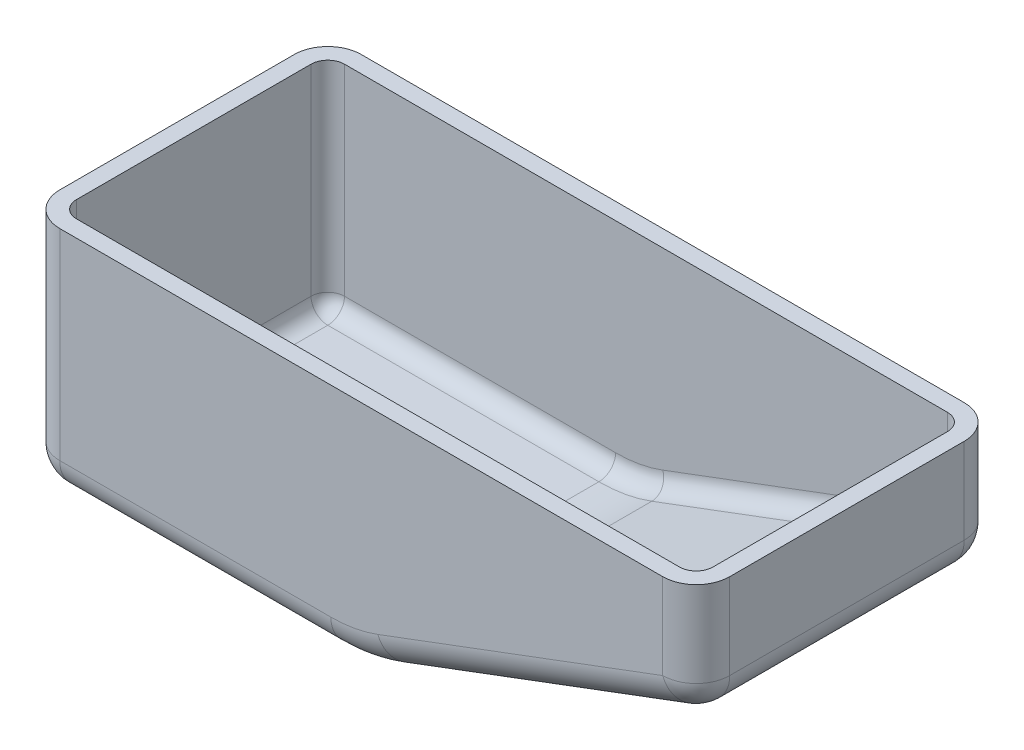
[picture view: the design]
ISO-10303-21;
HEADER;
FILE_DESCRIPTION(('STEP AP214'),'2;1');
FILE_NAME('part.step','',(''),(''),'','','');
FILE_SCHEMA(('AUTOMOTIVE_DESIGN { 1 0 10303 214 1 1 1 1 }'));
ENDSEC;
DATA;
#1=APPLICATION_CONTEXT('core data for automotive mechanical design processes');
#2=APPLICATION_PROTOCOL_DEFINITION('international standard','automotive_design',2000,#1);
#3=PRODUCT_CONTEXT('',#1,'mechanical');
#4=PRODUCT('Part','Part','',(#3));
#5=PRODUCT_RELATED_PRODUCT_CATEGORY('part','',(#4));
#6=PRODUCT_DEFINITION_FORMATION('','',#4);
#7=PRODUCT_DEFINITION_CONTEXT('part definition',#1,'design');
#8=PRODUCT_DEFINITION('design','',#6,#7);
#9=PRODUCT_DEFINITION_SHAPE('','',#8);
#10=(LENGTH_UNIT() NAMED_UNIT(*) SI_UNIT(.MILLI.,.METRE.));
#11=(NAMED_UNIT(*) PLANE_ANGLE_UNIT() SI_UNIT($,.RADIAN.));
#12=(NAMED_UNIT(*) SI_UNIT($,.STERADIAN.) SOLID_ANGLE_UNIT());
#13=UNCERTAINTY_MEASURE_WITH_UNIT(LENGTH_MEASURE(1.E-05),#10,'distance_accuracy_value','');
#14=(GEOMETRIC_REPRESENTATION_CONTEXT(3) GLOBAL_UNCERTAINTY_ASSIGNED_CONTEXT((#13)) GLOBAL_UNIT_ASSIGNED_CONTEXT((#10,
#11,#12)) REPRESENTATION_CONTEXT('',''));
#15=CARTESIAN_POINT('',(0.,0.,0.));
#16=DIRECTION('',(0.,0.,1.));
#17=DIRECTION('',(1.,0.,0.));
#18=AXIS2_PLACEMENT_3D('',#15,#16,#17);
#19=CARTESIAN_POINT('',(0.,0.,22.86));
#20=DIRECTION('',(0.,-1.,0.));
#21=DIRECTION('',(0.,0.,-1.));
#22=AXIS2_PLACEMENT_3D('',#19,#20,#21);
#23=PLANE('',#22);
#24=DIRECTION('',(0.,0.,-1.));
#25=VECTOR('',#24,1.);
#26=CARTESIAN_POINT('',(0.,0.,22.86));
#27=LINE('',#26,#25);
#28=CARTESIAN_POINT('',(0.,0.,17.78));
#29=VERTEX_POINT('',#28);
#30=CARTESIAN_POINT('',(0.,0.,-17.78));
#31=VERTEX_POINT('',#30);
#32=EDGE_CURVE('E352',#29,#31,#27,.T.);
#33=ORIENTED_EDGE('',*,*,#32,.F.);
#34=CARTESIAN_POINT('',(5.08,0.,17.78));
#35=DIRECTION('',(0.,-1.,0.));
#36=DIRECTION('',(0.,0.,-1.));
#37=AXIS2_PLACEMENT_3D('',#34,#35,#36);
#38=CIRCLE('',#37,5.08);
#39=CARTESIAN_POINT('',(5.08,0.,22.86));
#40=VERTEX_POINT('',#39);
#41=EDGE_CURVE('E421',#29,#40,#38,.F.);
#42=ORIENTED_EDGE('',*,*,#41,.T.);
#43=DIRECTION('',(-1.,0.,0.));
#44=VECTOR('',#43,1.);
#45=CARTESIAN_POINT('',(0.,0.,22.86));
#46=LINE('',#45,#44);
#47=CARTESIAN_POINT('',(96.52,0.,22.86));
#48=VERTEX_POINT('',#47);
#49=EDGE_CURVE('E348',#48,#40,#46,.T.);
#50=ORIENTED_EDGE('',*,*,#49,.F.);
#51=CARTESIAN_POINT('',(96.52,0.,17.78));
#52=DIRECTION('',(0.,-1.,0.));
#53=DIRECTION('',(0.,0.,-1.));
#54=AXIS2_PLACEMENT_3D('',#51,#52,#53);
#55=CIRCLE('',#54,5.08);
#56=CARTESIAN_POINT('',(101.6,0.,17.78));
#57=VERTEX_POINT('',#56);
#58=EDGE_CURVE('E418',#48,#57,#55,.F.);
#59=ORIENTED_EDGE('',*,*,#58,.T.);
#60=DIRECTION('',(0.,0.,-1.));
#61=VECTOR('',#60,1.);
#62=CARTESIAN_POINT('',(101.6,0.,22.86));
#63=LINE('',#62,#61);
#64=CARTESIAN_POINT('',(101.6,0.,-17.78));
#65=VERTEX_POINT('',#64);
#66=EDGE_CURVE('E361',#57,#65,#63,.T.);
#67=ORIENTED_EDGE('',*,*,#66,.T.);
#68=CARTESIAN_POINT('',(96.52,0.,-17.78));
#69=DIRECTION('',(0.,-1.,0.));
#70=DIRECTION('',(0.,0.,-1.));
#71=AXIS2_PLACEMENT_3D('',#68,#69,#70);
#72=CIRCLE('',#71,5.08);
#73=CARTESIAN_POINT('',(96.52,0.,-22.86));
#74=VERTEX_POINT('',#73);
#75=EDGE_CURVE('E412',#65,#74,#72,.F.);
#76=ORIENTED_EDGE('',*,*,#75,.T.);
#77=DIRECTION('',(-1.,0.,0.));
#78=VECTOR('',#77,1.);
#79=CARTESIAN_POINT('',(0.,0.,-22.86));
#80=LINE('',#79,#78);
#81=CARTESIAN_POINT('',(5.08,0.,-22.86));
#82=VERTEX_POINT('',#81);
#83=EDGE_CURVE('E353',#74,#82,#80,.T.);
#84=ORIENTED_EDGE('',*,*,#83,.T.);
#85=CARTESIAN_POINT('',(5.08,0.,-17.78));
#86=DIRECTION('',(0.,-1.,0.));
#87=DIRECTION('',(0.,0.,-1.));
#88=AXIS2_PLACEMENT_3D('',#85,#86,#87);
#89=CIRCLE('',#88,5.08);
#90=EDGE_CURVE('E415',#82,#31,#89,.F.);
#91=ORIENTED_EDGE('',*,*,#90,.T.);
#92=EDGE_LOOP('',(#33,#42,#50,#59,#67,#76,#84,#91));
#93=FACE_BOUND('',#92,.T.);
#94=CARTESIAN_POINT('',(5.08,0.,17.78));
#95=DIRECTION('',(0.,-1.,0.));
#96=DIRECTION('',(0.,0.,-1.));
#97=AXIS2_PLACEMENT_3D('',#94,#95,#96);
#98=CIRCLE('',#97,2.54);
#99=CARTESIAN_POINT('',(2.54,0.,17.78));
#100=VERTEX_POINT('',#99);
#101=CARTESIAN_POINT('',(5.08,0.,20.32));
#102=VERTEX_POINT('',#101);
#103=EDGE_CURVE('E327',#100,#102,#98,.F.);
#104=ORIENTED_EDGE('',*,*,#103,.F.);
#105=DIRECTION('',(0.,0.,-1.));
#106=VECTOR('',#105,1.);
#107=CARTESIAN_POINT('',(2.54,0.,22.86));
#108=LINE('',#107,#106);
#109=CARTESIAN_POINT('',(2.54,0.,-17.78));
#110=VERTEX_POINT('',#109);
#111=EDGE_CURVE('E265',#100,#110,#108,.T.);
#112=ORIENTED_EDGE('',*,*,#111,.T.);
#113=CARTESIAN_POINT('',(5.08,0.,-17.78));
#114=DIRECTION('',(0.,-1.,0.));
#115=DIRECTION('',(0.,0.,-1.));
#116=AXIS2_PLACEMENT_3D('',#113,#114,#115);
#117=CIRCLE('',#116,2.54);
#118=CARTESIAN_POINT('',(5.08,0.,-20.32));
#119=VERTEX_POINT('',#118);
#120=EDGE_CURVE('E336',#119,#110,#117,.F.);
#121=ORIENTED_EDGE('',*,*,#120,.F.);
#122=DIRECTION('',(-1.,0.,0.));
#123=VECTOR('',#122,1.);
#124=CARTESIAN_POINT('',(0.,0.,-20.32));
#125=LINE('',#124,#123);
#126=CARTESIAN_POINT('',(96.52,0.,-20.32));
#127=VERTEX_POINT('',#126);
#128=EDGE_CURVE('E64',#127,#119,#125,.T.);
#129=ORIENTED_EDGE('',*,*,#128,.F.);
#130=CARTESIAN_POINT('',(96.52,0.,-17.78));
#131=DIRECTION('',(0.,-1.,0.));
#132=DIRECTION('',(0.,0.,-1.));
#133=AXIS2_PLACEMENT_3D('',#130,#131,#132);
#134=CIRCLE('',#133,2.54);
#135=CARTESIAN_POINT('',(99.06,0.,-17.78));
#136=VERTEX_POINT('',#135);
#137=EDGE_CURVE('E269',#136,#127,#134,.F.);
#138=ORIENTED_EDGE('',*,*,#137,.F.);
#139=DIRECTION('',(0.,0.,-1.));
#140=VECTOR('',#139,1.);
#141=CARTESIAN_POINT('',(99.06,0.,22.86));
#142=LINE('',#141,#140);
#143=CARTESIAN_POINT('',(99.06,0.,17.78));
#144=VERTEX_POINT('',#143);
#145=EDGE_CURVE('E325',#144,#136,#142,.T.);
#146=ORIENTED_EDGE('',*,*,#145,.F.);
#147=CARTESIAN_POINT('',(96.52,0.,17.78));
#148=DIRECTION('',(0.,-1.,0.));
#149=DIRECTION('',(0.,0.,-1.));
#150=AXIS2_PLACEMENT_3D('',#147,#148,#149);
#151=CIRCLE('',#150,2.54);
#152=CARTESIAN_POINT('',(96.52,0.,20.32));
#153=VERTEX_POINT('',#152);
#154=EDGE_CURVE('E330',#153,#144,#151,.F.);
#155=ORIENTED_EDGE('',*,*,#154,.F.);
#156=DIRECTION('',(-1.,0.,0.));
#157=VECTOR('',#156,1.);
#158=CARTESIAN_POINT('',(0.,0.,20.32));
#159=LINE('',#158,#157);
#160=EDGE_CURVE('E326',#153,#102,#159,.T.);
#161=ORIENTED_EDGE('',*,*,#160,.T.);
#162=EDGE_LOOP('',(#104,#112,#121,#129,#138,#146,#155,#161));
#163=FACE_BOUND('',#162,.T.);
#164=ADVANCED_FACE('F46',(#93,#163),#23,.F.);
#165=CARTESIAN_POINT('',(0.,-35.56,22.86));
#166=DIRECTION('',(1.,0.,0.));
#167=DIRECTION('',(0.,0.,-1.));
#168=AXIS2_PLACEMENT_3D('',#165,#166,#167);
#169=PLANE('',#168);
#170=DIRECTION('',(0.,0.,-1.));
#171=VECTOR('',#170,1.);
#172=CARTESIAN_POINT('',(0.,-30.48,22.86));
#173=LINE('',#172,#171);
#174=CARTESIAN_POINT('',(0.,-30.48,-17.78));
#175=VERTEX_POINT('',#174);
#176=CARTESIAN_POINT('',(0.,-30.48,17.78));
#177=VERTEX_POINT('',#176);
#178=EDGE_CURVE('E385',#175,#177,#173,.F.);
#179=ORIENTED_EDGE('',*,*,#178,.T.);
#180=DIRECTION('',(0.,-1.,0.));
#181=VECTOR('',#180,1.);
#182=CARTESIAN_POINT('',(0.,-35.56,17.78));
#183=LINE('',#182,#181);
#184=EDGE_CURVE('E409',#177,#29,#183,.F.);
#185=ORIENTED_EDGE('',*,*,#184,.T.);
#186=ORIENTED_EDGE('',*,*,#32,.T.);
#187=DIRECTION('',(0.,-1.,0.));
#188=VECTOR('',#187,1.);
#189=CARTESIAN_POINT('',(0.,-30.48,-17.78));
#190=LINE('',#189,#188);
#191=EDGE_CURVE('E405',#31,#175,#190,.T.);
#192=ORIENTED_EDGE('',*,*,#191,.T.);
#193=EDGE_LOOP('',(#179,#185,#186,#192));
#194=FACE_BOUND('',#193,.T.);
#195=ADVANCED_FACE('F582',(#194),#169,.F.);
#196=CARTESIAN_POINT('',(50.8,-35.56,22.86));
#197=DIRECTION('',(0.,1.,0.));
#198=DIRECTION('',(-1.,0.,0.));
#199=AXIS2_PLACEMENT_3D('',#196,#197,#198);
#200=PLANE('',#199);
#201=DIRECTION('',(0.,0.,-1.));
#202=VECTOR('',#201,1.);
#203=CARTESIAN_POINT('',(46.1941016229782,-35.56,22.86));
#204=LINE('',#203,#202);
#205=CARTESIAN_POINT('',(46.1941016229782,-35.56,-17.78));
#206=VERTEX_POINT('',#205);
#207=CARTESIAN_POINT('',(46.1941016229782,-35.56,17.78));
#208=VERTEX_POINT('',#207);
#209=EDGE_CURVE('E377',#206,#208,#204,.F.);
#210=ORIENTED_EDGE('',*,*,#209,.T.);
#211=DIRECTION('',(1.,0.,0.));
#212=VECTOR('',#211,1.);
#213=CARTESIAN_POINT('',(50.8,-35.56,17.78));
#214=LINE('',#213,#212);
#215=CARTESIAN_POINT('',(5.08,-35.56,17.78));
#216=VERTEX_POINT('',#215);
#217=EDGE_CURVE('E433',#208,#216,#214,.F.);
#218=ORIENTED_EDGE('',*,*,#217,.T.);
#219=DIRECTION('',(0.,0.,-1.));
#220=VECTOR('',#219,1.);
#221=CARTESIAN_POINT('',(5.08,-35.56,22.86));
#222=LINE('',#221,#220);
#223=CARTESIAN_POINT('',(5.08,-35.56,-17.78));
#224=VERTEX_POINT('',#223);
#225=EDGE_CURVE('E381',#216,#224,#222,.T.);
#226=ORIENTED_EDGE('',*,*,#225,.T.);
#227=DIRECTION('',(1.,0.,0.));
#228=VECTOR('',#227,1.);
#229=CARTESIAN_POINT('',(46.1941016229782,-35.56,-17.78));
#230=LINE('',#229,#228);
#231=EDGE_CURVE('E430',#224,#206,#230,.T.);
#232=ORIENTED_EDGE('',*,*,#231,.T.);
#233=EDGE_LOOP('',(#210,#218,#226,#232));
#234=FACE_BOUND('',#233,.T.);
#235=ADVANCED_FACE('F562',(#234),#200,.F.);
#236=CARTESIAN_POINT('',(101.6,-16.51,22.86));
#237=DIRECTION('',(-0.351123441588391,0.936329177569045,0.));
#238=DIRECTION('',(-0.936329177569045,-0.351123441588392,0.));
#239=AXIS2_PLACEMENT_3D('',#236,#237,#238);
#240=PLANE('',#239);
#241=DIRECTION('',(0.,0.,-1.));
#242=VECTOR('',#241,1.);
#243=CARTESIAN_POINT('',(55.1126370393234,-33.9427611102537,22.86));
#244=LINE('',#243,#242);
#245=CARTESIAN_POINT('',(55.1126370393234,-33.9427611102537,17.78));
#246=VERTEX_POINT('',#245);
#247=CARTESIAN_POINT('',(55.1126370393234,-33.9427611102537,-17.78));
#248=VERTEX_POINT('',#247);
#249=EDGE_CURVE('E369',#246,#248,#244,.T.);
#250=ORIENTED_EDGE('',*,*,#249,.T.);
#251=DIRECTION('',(0.936329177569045,0.351123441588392,0.));
#252=VECTOR('',#251,1.);
#253=CARTESIAN_POINT('',(98.303707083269,-17.7461098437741,-17.78));
#254=LINE('',#253,#252);
#255=CARTESIAN_POINT('',(98.303707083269,-17.7461098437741,-17.78));
#256=VERTEX_POINT('',#255);
#257=EDGE_CURVE('E12',#248,#256,#254,.T.);
#258=ORIENTED_EDGE('',*,*,#257,.T.);
#259=DIRECTION('',(0.,0.,-1.));
#260=VECTOR('',#259,1.);
#261=CARTESIAN_POINT('',(98.303707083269,-17.7461098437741,22.86));
#262=LINE('',#261,#260);
#263=CARTESIAN_POINT('',(98.303707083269,-17.7461098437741,17.78));
#264=VERTEX_POINT('',#263);
#265=EDGE_CURVE('E373',#256,#264,#262,.F.);
#266=ORIENTED_EDGE('',*,*,#265,.T.);
#267=DIRECTION('',(0.936329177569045,0.351123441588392,0.));
#268=VECTOR('',#267,1.);
#269=CARTESIAN_POINT('',(101.6,-16.51,17.78));
#270=LINE('',#269,#268);
#271=EDGE_CURVE('E56',#264,#246,#270,.F.);
#272=ORIENTED_EDGE('',*,*,#271,.T.);
#273=EDGE_LOOP('',(#250,#258,#266,#272));
#274=FACE_BOUND('',#273,.T.);
#275=ADVANCED_FACE('F542',(#274),#240,.F.);
#276=CARTESIAN_POINT('',(101.6,0.,22.86));
#277=DIRECTION('',(-1.,0.,0.));
#278=DIRECTION('',(0.,0.,1.));
#279=AXIS2_PLACEMENT_3D('',#276,#277,#278);
#280=PLANE('',#279);
#281=ORIENTED_EDGE('',*,*,#66,.F.);
#282=DIRECTION('',(0.,1.,0.));
#283=VECTOR('',#282,1.);
#284=CARTESIAN_POINT('',(101.6,0.,17.78));
#285=LINE('',#284,#283);
#286=CARTESIAN_POINT('',(101.6,-12.9895576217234,17.78));
#287=VERTEX_POINT('',#286);
#288=EDGE_CURVE('E445',#57,#287,#285,.F.);
#289=ORIENTED_EDGE('',*,*,#288,.T.);
#290=DIRECTION('',(0.,0.,-1.));
#291=VECTOR('',#290,1.);
#292=CARTESIAN_POINT('',(101.6,-12.9895576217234,22.86));
#293=LINE('',#292,#291);
#294=CARTESIAN_POINT('',(101.6,-12.9895576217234,-17.78));
#295=VERTEX_POINT('',#294);
#296=EDGE_CURVE('E365',#287,#295,#293,.T.);
#297=ORIENTED_EDGE('',*,*,#296,.T.);
#298=DIRECTION('',(0.,1.,0.));
#299=VECTOR('',#298,1.);
#300=CARTESIAN_POINT('',(101.6,0.,-17.78));
#301=LINE('',#300,#299);
#302=EDGE_CURVE('E442',#295,#65,#301,.T.);
#303=ORIENTED_EDGE('',*,*,#302,.T.);
#304=EDGE_LOOP('',(#281,#289,#297,#303));
#305=FACE_BOUND('',#304,.T.);
#306=ADVANCED_FACE('F524',(#305),#280,.F.);
#307=CARTESIAN_POINT('',(0.,0.,22.86));
#308=DIRECTION('',(0.,0.,-1.));
#309=DIRECTION('',(-1.,0.,0.));
#310=AXIS2_PLACEMENT_3D('',#307,#308,#309);
#311=PLANE('',#310);
#312=ORIENTED_EDGE('',*,*,#49,.T.);
#313=DIRECTION('',(0.,-1.,0.));
#314=VECTOR('',#313,1.);
#315=CARTESIAN_POINT('',(5.08,0.,22.86));
#316=LINE('',#315,#314);
#317=CARTESIAN_POINT('',(5.08,-30.48,22.86));
#318=VERTEX_POINT('',#317);
#319=EDGE_CURVE('E401',#40,#318,#316,.T.);
#320=ORIENTED_EDGE('',*,*,#319,.T.);
#321=DIRECTION('',(1.,0.,0.));
#322=VECTOR('',#321,1.);
#323=CARTESIAN_POINT('',(0.,-30.48,22.86));
#324=LINE('',#323,#322);
#325=CARTESIAN_POINT('',(46.1941016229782,-30.48,22.86));
#326=VERTEX_POINT('',#325);
#327=EDGE_CURVE('E398',#318,#326,#324,.T.);
#328=ORIENTED_EDGE('',*,*,#327,.T.);
#329=CARTESIAN_POINT('',(46.1941016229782,-10.16,22.86));
#330=DIRECTION('',(0.,0.,-1.));
#331=DIRECTION('',(-1.,0.,0.));
#332=AXIS2_PLACEMENT_3D('',#329,#330,#331);
#333=CIRCLE('',#332,20.32);
#334=CARTESIAN_POINT('',(53.3289299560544,-29.186208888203,22.86));
#335=VERTEX_POINT('',#334);
#336=EDGE_CURVE('E395',#326,#335,#333,.F.);
#337=ORIENTED_EDGE('',*,*,#336,.T.);
#338=DIRECTION('',(0.936329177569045,0.351123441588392,0.));
#339=VECTOR('',#338,1.);
#340=CARTESIAN_POINT('',(16.1702655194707,-43.1207080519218,22.86));
#341=LINE('',#340,#339);
#342=CARTESIAN_POINT('',(96.52,-12.9895576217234,22.86));
#343=VERTEX_POINT('',#342);
#344=EDGE_CURVE('E389',#335,#343,#341,.T.);
#345=ORIENTED_EDGE('',*,*,#344,.T.);
#346=DIRECTION('',(0.,1.,0.));
#347=VECTOR('',#346,1.);
#348=CARTESIAN_POINT('',(96.52,0.,22.86));
#349=LINE('',#348,#347);
#350=EDGE_CURVE('E392',#343,#48,#349,.T.);
#351=ORIENTED_EDGE('',*,*,#350,.T.);
#352=EDGE_LOOP('',(#312,#320,#328,#337,#345,#351));
#353=FACE_BOUND('',#352,.T.);
#354=ADVANCED_FACE('F597',(#353),#311,.F.);
#355=CARTESIAN_POINT('',(0.,0.,-22.86));
#356=DIRECTION('',(0.,0.,-1.));
#357=DIRECTION('',(-1.,0.,0.));
#358=AXIS2_PLACEMENT_3D('',#355,#356,#357);
#359=PLANE('',#358);
#360=DIRECTION('',(1.,0.,0.));
#361=VECTOR('',#360,1.);
#362=CARTESIAN_POINT('',(5.08,-30.48,-22.86));
#363=LINE('',#362,#361);
#364=CARTESIAN_POINT('',(46.1941016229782,-30.48,-22.86));
#365=VERTEX_POINT('',#364);
#366=CARTESIAN_POINT('',(5.08,-30.48,-22.86));
#367=VERTEX_POINT('',#366);
#368=EDGE_CURVE('E454',#365,#367,#363,.F.);
#369=ORIENTED_EDGE('',*,*,#368,.T.);
#370=DIRECTION('',(0.,-1.,0.));
#371=VECTOR('',#370,1.);
#372=CARTESIAN_POINT('',(5.08,0.,-22.86));
#373=LINE('',#372,#371);
#374=EDGE_CURVE('E465',#367,#82,#373,.F.);
#375=ORIENTED_EDGE('',*,*,#374,.T.);
#376=ORIENTED_EDGE('',*,*,#83,.F.);
#377=DIRECTION('',(0.,1.,0.));
#378=VECTOR('',#377,1.);
#379=CARTESIAN_POINT('',(96.52,-12.9895576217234,-22.86));
#380=LINE('',#379,#378);
#381=CARTESIAN_POINT('',(96.52,-12.9895576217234,-22.86));
#382=VERTEX_POINT('',#381);
#383=EDGE_CURVE('E72',#74,#382,#380,.F.);
#384=ORIENTED_EDGE('',*,*,#383,.T.);
#385=DIRECTION('',(0.936329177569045,0.351123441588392,0.));
#386=VECTOR('',#385,1.);
#387=CARTESIAN_POINT('',(53.3289299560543,-29.186208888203,-22.86));
#388=LINE('',#387,#386);
#389=CARTESIAN_POINT('',(53.3289299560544,-29.186208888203,-22.86));
#390=VERTEX_POINT('',#389);
#391=EDGE_CURVE('E460',#382,#390,#388,.F.);
#392=ORIENTED_EDGE('',*,*,#391,.T.);
#393=CARTESIAN_POINT('',(46.1941016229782,-10.16,-22.86));
#394=DIRECTION('',(0.,0.,-1.));
#395=DIRECTION('',(-1.,0.,0.));
#396=AXIS2_PLACEMENT_3D('',#393,#394,#395);
#397=CIRCLE('',#396,20.32);
#398=EDGE_CURVE('E457',#390,#365,#397,.T.);
#399=ORIENTED_EDGE('',*,*,#398,.T.);
#400=EDGE_LOOP('',(#369,#375,#376,#384,#392,#399));
#401=FACE_BOUND('',#400,.T.);
#402=ADVANCED_FACE('F579',(#401),#359,.T.);
#403=CARTESIAN_POINT('',(96.52,-12.9895576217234,22.86));
#404=DIRECTION('',(0.,0.,-1.));
#405=DIRECTION('',(-1.,0.,0.));
#406=AXIS2_PLACEMENT_3D('',#403,#404,#405);
#407=CYLINDRICAL_SURFACE('',#406,5.08);
#408=ORIENTED_EDGE('',*,*,#296,.F.);
#409=CARTESIAN_POINT('',(96.52,-12.9895576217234,17.78));
#410=DIRECTION('',(0.,0.,-1.));
#411=DIRECTION('',(-1.,0.,0.));
#412=AXIS2_PLACEMENT_3D('',#409,#410,#411);
#413=CIRCLE('',#412,5.08);
#414=EDGE_CURVE('E451',#287,#264,#413,.T.);
#415=ORIENTED_EDGE('',*,*,#414,.T.);
#416=ORIENTED_EDGE('',*,*,#265,.F.);
#417=CARTESIAN_POINT('',(96.52,-12.9895576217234,-17.78));
#418=DIRECTION('',(0.,0.,-1.));
#419=DIRECTION('',(-1.,0.,0.));
#420=AXIS2_PLACEMENT_3D('',#417,#418,#419);
#421=CIRCLE('',#420,5.08);
#422=EDGE_CURVE('E448',#256,#295,#421,.F.);
#423=ORIENTED_EDGE('',*,*,#422,.T.);
#424=EDGE_LOOP('',(#408,#415,#416,#423));
#425=FACE_BOUND('',#424,.T.);
#426=ADVANCED_FACE('F538',(#425),#407,.T.);
#427=CARTESIAN_POINT('',(5.08,-30.48,22.86));
#428=DIRECTION('',(0.,0.,-1.));
#429=DIRECTION('',(-1.,0.,0.));
#430=AXIS2_PLACEMENT_3D('',#427,#428,#429);
#431=CYLINDRICAL_SURFACE('',#430,5.08);
#432=ORIENTED_EDGE('',*,*,#225,.F.);
#433=CARTESIAN_POINT('',(5.08,-30.48,17.78));
#434=DIRECTION('',(0.,0.,-1.));
#435=DIRECTION('',(-1.,0.,0.));
#436=AXIS2_PLACEMENT_3D('',#433,#434,#435);
#437=CIRCLE('',#436,5.08);
#438=EDGE_CURVE('E427',#216,#177,#437,.T.);
#439=ORIENTED_EDGE('',*,*,#438,.T.);
#440=ORIENTED_EDGE('',*,*,#178,.F.);
#441=CARTESIAN_POINT('',(5.08,-30.48,-17.78));
#442=DIRECTION('',(0.,0.,-1.));
#443=DIRECTION('',(-1.,0.,0.));
#444=AXIS2_PLACEMENT_3D('',#441,#442,#443);
#445=CIRCLE('',#444,5.08);
#446=EDGE_CURVE('E424',#175,#224,#445,.F.);
#447=ORIENTED_EDGE('',*,*,#446,.T.);
#448=EDGE_LOOP('',(#432,#439,#440,#447));
#449=FACE_BOUND('',#448,.T.);
#450=ADVANCED_FACE('F620',(#449),#431,.T.);
#451=CARTESIAN_POINT('',(46.1941016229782,-10.16,22.86));
#452=DIRECTION('',(0.,0.,-1.));
#453=DIRECTION('',(-1.,0.,0.));
#454=AXIS2_PLACEMENT_3D('',#451,#452,#453);
#455=CYLINDRICAL_SURFACE('',#454,25.4);
#456=ORIENTED_EDGE('',*,*,#249,.F.);
#457=CARTESIAN_POINT('',(46.1941016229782,-10.16,17.78));
#458=DIRECTION('',(0.,0.,-1.));
#459=DIRECTION('',(-1.,0.,0.));
#460=AXIS2_PLACEMENT_3D('',#457,#458,#459);
#461=CIRCLE('',#460,25.4);
#462=EDGE_CURVE('E439',#246,#208,#461,.T.);
#463=ORIENTED_EDGE('',*,*,#462,.T.);
#464=ORIENTED_EDGE('',*,*,#209,.F.);
#465=CARTESIAN_POINT('',(46.1941016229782,-10.16,-17.78));
#466=DIRECTION('',(0.,0.,-1.));
#467=DIRECTION('',(-1.,0.,0.));
#468=AXIS2_PLACEMENT_3D('',#465,#466,#467);
#469=CIRCLE('',#468,25.4);
#470=EDGE_CURVE('E436',#206,#248,#469,.F.);
#471=ORIENTED_EDGE('',*,*,#470,.T.);
#472=EDGE_LOOP('',(#456,#463,#464,#471));
#473=FACE_BOUND('',#472,.T.);
#474=ADVANCED_FACE('F559',(#473),#455,.T.);
#475=CARTESIAN_POINT('',(96.52,0.,17.78));
#476=DIRECTION('',(0.,1.,0.));
#477=DIRECTION('',(0.,0.,1.));
#478=AXIS2_PLACEMENT_3D('',#475,#476,#477);
#479=CYLINDRICAL_SURFACE('',#478,5.08);
#480=CARTESIAN_POINT('',(96.52,-12.9895576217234,17.78));
#481=DIRECTION('',(0.,-1.,0.));
#482=DIRECTION('',(0.,0.,-1.));
#483=AXIS2_PLACEMENT_3D('',#480,#481,#482);
#484=CIRCLE('',#483,5.08);
#485=EDGE_CURVE('E357',#287,#343,#484,.T.);
#486=ORIENTED_EDGE('',*,*,#485,.F.);
#487=ORIENTED_EDGE('',*,*,#288,.F.);
#488=ORIENTED_EDGE('',*,*,#58,.F.);
#489=ORIENTED_EDGE('',*,*,#350,.F.);
#490=EDGE_LOOP('',(#486,#487,#488,#489));
#491=FACE_BOUND('',#490,.T.);
#492=ADVANCED_FACE('F535',(#491),#479,.T.);
#493=CARTESIAN_POINT('',(96.52,-12.9895576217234,17.78));
#494=DIRECTION('',(0.,0.,-1.));
#495=DIRECTION('',(-1.,0.,0.));
#496=AXIS2_PLACEMENT_3D('',#493,#494,#495);
#497=SPHERICAL_SURFACE('',#496,5.08);
#498=ORIENTED_EDGE('',*,*,#414,.F.);
#499=ORIENTED_EDGE('',*,*,#485,.T.);
#500=CARTESIAN_POINT('',(96.52,-12.9895576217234,17.78));
#501=DIRECTION('',(-0.936329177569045,-0.351123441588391,0.));
#502=DIRECTION('',(0.351123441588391,-0.936329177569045,0.));
#503=AXIS2_PLACEMENT_3D('',#500,#501,#502);
#504=CIRCLE('',#503,5.08);
#505=EDGE_CURVE('E485',#264,#343,#504,.T.);
#506=ORIENTED_EDGE('',*,*,#505,.F.);
#507=EDGE_LOOP('',(#498,#499,#506));
#508=FACE_BOUND('',#507,.T.);
#509=ADVANCED_FACE('F546',(#508),#497,.T.);
#510=CARTESIAN_POINT('',(16.1702655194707,-43.1207080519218,17.78));
#511=DIRECTION('',(0.936329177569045,0.351123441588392,0.));
#512=DIRECTION('',(-0.351123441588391,0.936329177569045,0.));
#513=AXIS2_PLACEMENT_3D('',#510,#511,#512);
#514=CYLINDRICAL_SURFACE('',#513,5.08);
#515=ORIENTED_EDGE('',*,*,#505,.T.);
#516=ORIENTED_EDGE('',*,*,#344,.F.);
#517=CARTESIAN_POINT('',(53.3289299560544,-29.186208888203,17.78));
#518=DIRECTION('',(-0.936329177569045,-0.351123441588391,0.));
#519=DIRECTION('',(0.351123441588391,-0.936329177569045,0.));
#520=AXIS2_PLACEMENT_3D('',#517,#518,#519);
#521=CIRCLE('',#520,5.08);
#522=EDGE_CURVE('E481',#246,#335,#521,.T.);
#523=ORIENTED_EDGE('',*,*,#522,.F.);
#524=ORIENTED_EDGE('',*,*,#271,.F.);
#525=EDGE_LOOP('',(#515,#516,#523,#524));
#526=FACE_BOUND('',#525,.T.);
#527=ADVANCED_FACE('F550',(#526),#514,.T.);
#528=CARTESIAN_POINT('',(46.1941016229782,-10.16,17.78));
#529=DIRECTION('',(0.,0.,-1.));
#530=DIRECTION('',(-1.,0.,0.));
#531=AXIS2_PLACEMENT_3D('',#528,#529,#530);
#532=TOROIDAL_SURFACE('',#531,20.32,5.08);
#533=ORIENTED_EDGE('',*,*,#522,.T.);
#534=ORIENTED_EDGE('',*,*,#336,.F.);
#535=CARTESIAN_POINT('',(46.1941016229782,-30.48,17.78));
#536=DIRECTION('',(-1.,0.,0.));
#537=DIRECTION('',(0.,0.,1.));
#538=AXIS2_PLACEMENT_3D('',#535,#536,#537);
#539=CIRCLE('',#538,5.08);
#540=EDGE_CURVE('E477',#208,#326,#539,.T.);
#541=ORIENTED_EDGE('',*,*,#540,.F.);
#542=ORIENTED_EDGE('',*,*,#462,.F.);
#543=EDGE_LOOP('',(#533,#534,#541,#542));
#544=FACE_BOUND('',#543,.T.);
#545=ADVANCED_FACE('F555',(#544),#532,.T.);
#546=CARTESIAN_POINT('',(0.,-30.48,17.78));
#547=DIRECTION('',(1.,0.,0.));
#548=DIRECTION('',(0.,1.,0.));
#549=AXIS2_PLACEMENT_3D('',#546,#547,#548);
#550=CYLINDRICAL_SURFACE('',#549,5.08);
#551=CARTESIAN_POINT('',(5.08,-30.48,17.78));
#552=DIRECTION('',(-1.,0.,0.));
#553=DIRECTION('',(0.,0.,1.));
#554=AXIS2_PLACEMENT_3D('',#551,#552,#553);
#555=CIRCLE('',#554,5.08);
#556=EDGE_CURVE('E473',#216,#318,#555,.T.);
#557=ORIENTED_EDGE('',*,*,#556,.F.);
#558=ORIENTED_EDGE('',*,*,#217,.F.);
#559=ORIENTED_EDGE('',*,*,#540,.T.);
#560=ORIENTED_EDGE('',*,*,#327,.F.);
#561=EDGE_LOOP('',(#557,#558,#559,#560));
#562=FACE_BOUND('',#561,.T.);
#563=ADVANCED_FACE('F595',(#562),#550,.T.);
#564=CARTESIAN_POINT('',(5.08,-30.48,17.78));
#565=DIRECTION('',(0.,0.,-1.));
#566=DIRECTION('',(-1.,0.,0.));
#567=AXIS2_PLACEMENT_3D('',#564,#565,#566);
#568=SPHERICAL_SURFACE('',#567,5.08);
#569=ORIENTED_EDGE('',*,*,#438,.F.);
#570=ORIENTED_EDGE('',*,*,#556,.T.);
#571=CARTESIAN_POINT('',(5.08,-30.48,17.78));
#572=DIRECTION('',(0.,1.,0.));
#573=DIRECTION('',(0.,0.,1.));
#574=AXIS2_PLACEMENT_3D('',#571,#572,#573);
#575=CIRCLE('',#574,5.08);
#576=EDGE_CURVE('E470',#177,#318,#575,.T.);
#577=ORIENTED_EDGE('',*,*,#576,.F.);
#578=EDGE_LOOP('',(#569,#570,#577));
#579=FACE_BOUND('',#578,.T.);
#580=ADVANCED_FACE('F591',(#579),#568,.T.);
#581=CARTESIAN_POINT('',(5.08,0.,17.78));
#582=DIRECTION('',(0.,-1.,0.));
#583=DIRECTION('',(0.,0.,-1.));
#584=AXIS2_PLACEMENT_3D('',#581,#582,#583);
#585=CYLINDRICAL_SURFACE('',#584,5.08);
#586=ORIENTED_EDGE('',*,*,#41,.F.);
#587=ORIENTED_EDGE('',*,*,#184,.F.);
#588=ORIENTED_EDGE('',*,*,#576,.T.);
#589=ORIENTED_EDGE('',*,*,#319,.F.);
#590=EDGE_LOOP('',(#586,#587,#588,#589));
#591=FACE_BOUND('',#590,.T.);
#592=ADVANCED_FACE('F587',(#591),#585,.T.);
#593=CARTESIAN_POINT('',(96.52,0.,-17.78));
#594=DIRECTION('',(0.,-1.,0.));
#595=DIRECTION('',(0.,0.,-1.));
#596=AXIS2_PLACEMENT_3D('',#593,#594,#595);
#597=CYLINDRICAL_SURFACE('',#596,5.08);
#598=ORIENTED_EDGE('',*,*,#75,.F.);
#599=ORIENTED_EDGE('',*,*,#302,.F.);
#600=CARTESIAN_POINT('',(96.52,-12.9895576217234,-17.78));
#601=DIRECTION('',(0.,-1.,0.));
#602=DIRECTION('',(0.,0.,-1.));
#603=AXIS2_PLACEMENT_3D('',#600,#601,#602);
#604=CIRCLE('',#603,5.08);
#605=EDGE_CURVE('E50',#382,#295,#604,.T.);
#606=ORIENTED_EDGE('',*,*,#605,.F.);
#607=ORIENTED_EDGE('',*,*,#383,.F.);
#608=EDGE_LOOP('',(#598,#599,#606,#607));
#609=FACE_BOUND('',#608,.T.);
#610=ADVANCED_FACE('F48',(#609),#597,.T.);
#611=CARTESIAN_POINT('',(96.52,-12.9895576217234,-17.78));
#612=DIRECTION('',(0.,0.,-1.));
#613=DIRECTION('',(-1.,0.,0.));
#614=AXIS2_PLACEMENT_3D('',#611,#612,#613);
#615=SPHERICAL_SURFACE('',#614,5.08);
#616=ORIENTED_EDGE('',*,*,#605,.T.);
#617=ORIENTED_EDGE('',*,*,#422,.F.);
#618=CARTESIAN_POINT('',(96.52,-12.9895576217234,-17.78));
#619=DIRECTION('',(-0.936329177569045,-0.351123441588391,0.));
#620=DIRECTION('',(0.351123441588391,-0.936329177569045,0.));
#621=AXIS2_PLACEMENT_3D('',#618,#619,#620);
#622=CIRCLE('',#621,5.08);
#623=EDGE_CURVE('E507',#382,#256,#622,.T.);
#624=ORIENTED_EDGE('',*,*,#623,.F.);
#625=EDGE_LOOP('',(#616,#617,#624));
#626=FACE_BOUND('',#625,.T.);
#627=ADVANCED_FACE('F518',(#626),#615,.T.);
#628=CARTESIAN_POINT('',(99.816292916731,-11.7534477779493,-17.78));
#629=DIRECTION('',(-0.936329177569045,-0.351123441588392,0.));
#630=DIRECTION('',(0.351123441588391,-0.936329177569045,0.));
#631=AXIS2_PLACEMENT_3D('',#628,#629,#630);
#632=CYLINDRICAL_SURFACE('',#631,5.08);
#633=ORIENTED_EDGE('',*,*,#623,.T.);
#634=ORIENTED_EDGE('',*,*,#257,.F.);
#635=CARTESIAN_POINT('',(53.3289299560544,-29.186208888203,-17.78));
#636=DIRECTION('',(-0.936329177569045,-0.351123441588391,0.));
#637=DIRECTION('',(0.351123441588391,-0.936329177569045,0.));
#638=AXIS2_PLACEMENT_3D('',#635,#636,#637);
#639=CIRCLE('',#638,5.08);
#640=EDGE_CURVE('E504',#390,#248,#639,.T.);
#641=ORIENTED_EDGE('',*,*,#640,.F.);
#642=ORIENTED_EDGE('',*,*,#391,.F.);
#643=EDGE_LOOP('',(#633,#634,#641,#642));
#644=FACE_BOUND('',#643,.T.);
#645=ADVANCED_FACE('F649',(#644),#632,.T.);
#646=CARTESIAN_POINT('',(46.1941016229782,-10.16,-17.78));
#647=DIRECTION('',(0.,0.,-1.));
#648=DIRECTION('',(-1.,0.,0.));
#649=AXIS2_PLACEMENT_3D('',#646,#647,#648);
#650=TOROIDAL_SURFACE('',#649,20.32,5.08);
#651=ORIENTED_EDGE('',*,*,#640,.T.);
#652=ORIENTED_EDGE('',*,*,#470,.F.);
#653=CARTESIAN_POINT('',(46.1941016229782,-30.48,-17.78));
#654=DIRECTION('',(-1.,0.,0.));
#655=DIRECTION('',(0.,0.,1.));
#656=AXIS2_PLACEMENT_3D('',#653,#654,#655);
#657=CIRCLE('',#656,5.08);
#658=EDGE_CURVE('E500',#365,#206,#657,.T.);
#659=ORIENTED_EDGE('',*,*,#658,.F.);
#660=ORIENTED_EDGE('',*,*,#398,.F.);
#661=EDGE_LOOP('',(#651,#652,#659,#660));
#662=FACE_BOUND('',#661,.T.);
#663=ADVANCED_FACE('F646',(#662),#650,.T.);
#664=CARTESIAN_POINT('',(50.8,-30.48,-17.78));
#665=DIRECTION('',(-1.,0.,0.));
#666=DIRECTION('',(0.,-1.,0.));
#667=AXIS2_PLACEMENT_3D('',#664,#665,#666);
#668=CYLINDRICAL_SURFACE('',#667,5.08);
#669=ORIENTED_EDGE('',*,*,#658,.T.);
#670=ORIENTED_EDGE('',*,*,#231,.F.);
#671=CARTESIAN_POINT('',(5.08,-30.48,-17.78));
#672=DIRECTION('',(-1.,0.,0.));
#673=DIRECTION('',(0.,0.,1.));
#674=AXIS2_PLACEMENT_3D('',#671,#672,#673);
#675=CIRCLE('',#674,5.08);
#676=EDGE_CURVE('E495',#367,#224,#675,.T.);
#677=ORIENTED_EDGE('',*,*,#676,.F.);
#678=ORIENTED_EDGE('',*,*,#368,.F.);
#679=EDGE_LOOP('',(#669,#670,#677,#678));
#680=FACE_BOUND('',#679,.T.);
#681=ADVANCED_FACE('F567',(#680),#668,.T.);
#682=CARTESIAN_POINT('',(5.08,-30.48,-17.78));
#683=DIRECTION('',(0.,0.,-1.));
#684=DIRECTION('',(-1.,0.,0.));
#685=AXIS2_PLACEMENT_3D('',#682,#683,#684);
#686=SPHERICAL_SURFACE('',#685,5.08);
#687=ORIENTED_EDGE('',*,*,#676,.T.);
#688=ORIENTED_EDGE('',*,*,#446,.F.);
#689=CARTESIAN_POINT('',(5.08,-30.48,-17.78));
#690=DIRECTION('',(0.,1.,0.));
#691=DIRECTION('',(0.,0.,1.));
#692=AXIS2_PLACEMENT_3D('',#689,#690,#691);
#693=CIRCLE('',#692,5.08);
#694=EDGE_CURVE('E492',#367,#175,#693,.T.);
#695=ORIENTED_EDGE('',*,*,#694,.F.);
#696=EDGE_LOOP('',(#687,#688,#695));
#697=FACE_BOUND('',#696,.T.);
#698=ADVANCED_FACE('F574',(#697),#686,.T.);
#699=CARTESIAN_POINT('',(5.08,-35.56,-17.78));
#700=DIRECTION('',(0.,1.,0.));
#701=DIRECTION('',(0.,0.,1.));
#702=AXIS2_PLACEMENT_3D('',#699,#700,#701);
#703=CYLINDRICAL_SURFACE('',#702,5.08);
#704=ORIENTED_EDGE('',*,*,#90,.F.);
#705=ORIENTED_EDGE('',*,*,#374,.F.);
#706=ORIENTED_EDGE('',*,*,#694,.T.);
#707=ORIENTED_EDGE('',*,*,#191,.F.);
#708=EDGE_LOOP('',(#704,#705,#706,#707));
#709=FACE_BOUND('',#708,.T.);
#710=ADVANCED_FACE('F578',(#709),#703,.T.);
#711=CARTESIAN_POINT('',(2.54,-35.56,22.86));
#712=DIRECTION('',(1.,0.,0.));
#713=DIRECTION('',(0.,0.,-1.));
#714=AXIS2_PLACEMENT_3D('',#711,#712,#713);
#715=PLANE('',#714);
#716=DIRECTION('',(0.,0.,-1.));
#717=VECTOR('',#716,1.);
#718=CARTESIAN_POINT('',(2.54,-30.48,22.86));
#719=LINE('',#718,#717);
#720=CARTESIAN_POINT('',(2.54,-30.48,-17.78));
#721=VERTEX_POINT('',#720);
#722=CARTESIAN_POINT('',(2.54,-30.48,17.78));
#723=VERTEX_POINT('',#722);
#724=EDGE_CURVE('E251',#721,#723,#719,.F.);
#725=ORIENTED_EDGE('',*,*,#724,.F.);
#726=DIRECTION('',(0.,1.,0.));
#727=VECTOR('',#726,1.);
#728=CARTESIAN_POINT('',(2.54,-35.56,-17.78));
#729=LINE('',#728,#727);
#730=EDGE_CURVE('E270',#110,#721,#729,.F.);
#731=ORIENTED_EDGE('',*,*,#730,.F.);
#732=ORIENTED_EDGE('',*,*,#111,.F.);
#733=DIRECTION('',(0.,1.,0.));
#734=VECTOR('',#733,1.);
#735=CARTESIAN_POINT('',(2.54,-35.56,17.78));
#736=LINE('',#735,#734);
#737=EDGE_CURVE('E262',#723,#100,#736,.T.);
#738=ORIENTED_EDGE('',*,*,#737,.F.);
#739=EDGE_LOOP('',(#725,#731,#732,#738));
#740=FACE_BOUND('',#739,.T.);
#741=ADVANCED_FACE('F263',(#740),#715,.T.);
#742=CARTESIAN_POINT('',(50.8,-33.02,22.86));
#743=DIRECTION('',(0.,1.,0.));
#744=DIRECTION('',(-1.,0.,0.));
#745=AXIS2_PLACEMENT_3D('',#742,#743,#744);
#746=PLANE('',#745);
#747=DIRECTION('',(0.,0.,1.));
#748=VECTOR('',#747,1.);
#749=CARTESIAN_POINT('',(46.1941016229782,-33.02,22.86));
#750=LINE('',#749,#748);
#751=CARTESIAN_POINT('',(46.1941016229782,-33.02,-17.78));
#752=VERTEX_POINT('',#751);
#753=CARTESIAN_POINT('',(46.1941016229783,-33.02,17.78));
#754=VERTEX_POINT('',#753);
#755=EDGE_CURVE('E1081',#752,#754,#750,.T.);
#756=ORIENTED_EDGE('',*,*,#755,.F.);
#757=DIRECTION('',(-1.,0.,0.));
#758=VECTOR('',#757,1.);
#759=CARTESIAN_POINT('',(50.8,-33.02,-17.78));
#760=LINE('',#759,#758);
#761=CARTESIAN_POINT('',(5.08,-33.02,-17.78));
#762=VERTEX_POINT('',#761);
#763=EDGE_CURVE('E246',#762,#752,#760,.F.);
#764=ORIENTED_EDGE('',*,*,#763,.F.);
#765=DIRECTION('',(0.,0.,1.));
#766=VECTOR('',#765,1.);
#767=CARTESIAN_POINT('',(5.08,-33.02,22.86));
#768=LINE('',#767,#766);
#769=CARTESIAN_POINT('',(5.08,-33.02,17.78));
#770=VERTEX_POINT('',#769);
#771=EDGE_CURVE('E259',#770,#762,#768,.F.);
#772=ORIENTED_EDGE('',*,*,#771,.F.);
#773=DIRECTION('',(-1.,0.,0.));
#774=VECTOR('',#773,1.);
#775=CARTESIAN_POINT('',(50.8,-33.02,17.78));
#776=LINE('',#775,#774);
#777=EDGE_CURVE('E1077',#754,#770,#776,.T.);
#778=ORIENTED_EDGE('',*,*,#777,.F.);
#779=EDGE_LOOP('',(#756,#764,#772,#778));
#780=FACE_BOUND('',#779,.T.);
#781=ADVANCED_FACE('F808',(#780),#746,.T.);
#782=CARTESIAN_POINT('',(100.708146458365,-14.1317238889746,22.86));
#783=DIRECTION('',(-0.351123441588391,0.936329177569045,0.));
#784=DIRECTION('',(-0.936329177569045,-0.351123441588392,0.));
#785=AXIS2_PLACEMENT_3D('',#782,#783,#784);
#786=PLANE('',#785);
#787=DIRECTION('',(0.,0.,1.));
#788=VECTOR('',#787,1.);
#789=CARTESIAN_POINT('',(54.2207834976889,-31.5644849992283,22.86));
#790=LINE('',#789,#788);
#791=CARTESIAN_POINT('',(54.2207834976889,-31.5644849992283,17.78));
#792=VERTEX_POINT('',#791);
#793=CARTESIAN_POINT('',(54.2207834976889,-31.5644849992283,-17.78));
#794=VERTEX_POINT('',#793);
#795=EDGE_CURVE('E1093',#792,#794,#790,.F.);
#796=ORIENTED_EDGE('',*,*,#795,.F.);
#797=DIRECTION('',(-0.936329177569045,-0.351123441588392,0.));
#798=VECTOR('',#797,1.);
#799=CARTESIAN_POINT('',(100.708146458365,-14.1317238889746,17.78));
#800=LINE('',#799,#798);
#801=CARTESIAN_POINT('',(97.4118535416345,-15.3678337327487,17.78));
#802=VERTEX_POINT('',#801);
#803=EDGE_CURVE('E300',#802,#792,#800,.T.);
#804=ORIENTED_EDGE('',*,*,#803,.F.);
#805=DIRECTION('',(0.,0.,1.));
#806=VECTOR('',#805,1.);
#807=CARTESIAN_POINT('',(97.4118535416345,-15.3678337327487,22.86));
#808=LINE('',#807,#806);
#809=CARTESIAN_POINT('',(97.4118535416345,-15.3678337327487,-17.78));
#810=VERTEX_POINT('',#809);
#811=EDGE_CURVE('E1097',#810,#802,#808,.T.);
#812=ORIENTED_EDGE('',*,*,#811,.F.);
#813=DIRECTION('',(-0.936329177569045,-0.351123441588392,0.));
#814=VECTOR('',#813,1.);
#815=CARTESIAN_POINT('',(100.708146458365,-14.1317238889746,-17.78));
#816=LINE('',#815,#814);
#817=EDGE_CURVE('E496',#794,#810,#816,.F.);
#818=ORIENTED_EDGE('',*,*,#817,.F.);
#819=EDGE_LOOP('',(#796,#804,#812,#818));
#820=FACE_BOUND('',#819,.T.);
#821=ADVANCED_FACE('F816',(#820),#786,.T.);
#822=CARTESIAN_POINT('',(99.06,0.,22.86));
#823=DIRECTION('',(-1.,0.,0.));
#824=DIRECTION('',(0.,0.,1.));
#825=AXIS2_PLACEMENT_3D('',#822,#823,#824);
#826=PLANE('',#825);
#827=ORIENTED_EDGE('',*,*,#145,.T.);
#828=DIRECTION('',(0.,1.,0.));
#829=VECTOR('',#828,1.);
#830=CARTESIAN_POINT('',(99.06,0.,-17.78));
#831=LINE('',#830,#829);
#832=CARTESIAN_POINT('',(99.06,-12.9895576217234,-17.78));
#833=VERTEX_POINT('',#832);
#834=EDGE_CURVE('E1099',#833,#136,#831,.T.);
#835=ORIENTED_EDGE('',*,*,#834,.F.);
#836=DIRECTION('',(0.,0.,1.));
#837=VECTOR('',#836,1.);
#838=CARTESIAN_POINT('',(99.06,-12.9895576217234,22.86));
#839=LINE('',#838,#837);
#840=CARTESIAN_POINT('',(99.06,-12.9895576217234,17.78));
#841=VERTEX_POINT('',#840);
#842=EDGE_CURVE('E340',#841,#833,#839,.F.);
#843=ORIENTED_EDGE('',*,*,#842,.F.);
#844=DIRECTION('',(0.,1.,0.));
#845=VECTOR('',#844,1.);
#846=CARTESIAN_POINT('',(99.06,0.,17.78));
#847=LINE('',#846,#845);
#848=EDGE_CURVE('E1116',#144,#841,#847,.F.);
#849=ORIENTED_EDGE('',*,*,#848,.F.);
#850=EDGE_LOOP('',(#827,#835,#843,#849));
#851=FACE_BOUND('',#850,.T.);
#852=ADVANCED_FACE('F825',(#851),#826,.T.);
#853=CARTESIAN_POINT('',(0.,0.,20.32));
#854=DIRECTION('',(0.,0.,-1.));
#855=DIRECTION('',(-1.,0.,0.));
#856=AXIS2_PLACEMENT_3D('',#853,#854,#855);
#857=PLANE('',#856);
#858=ORIENTED_EDGE('',*,*,#160,.F.);
#859=DIRECTION('',(0.,1.,0.));
#860=VECTOR('',#859,1.);
#861=CARTESIAN_POINT('',(96.52,0.,20.32));
#862=LINE('',#861,#860);
#863=CARTESIAN_POINT('',(96.52,-12.9895576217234,20.32));
#864=VERTEX_POINT('',#863);
#865=EDGE_CURVE('E1054',#864,#153,#862,.T.);
#866=ORIENTED_EDGE('',*,*,#865,.F.);
#867=DIRECTION('',(0.936329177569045,0.351123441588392,0.));
#868=VECTOR('',#867,1.);
#869=CARTESIAN_POINT('',(16.1702655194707,-43.1207080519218,20.32));
#870=LINE('',#869,#868);
#871=CARTESIAN_POINT('',(53.3289299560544,-29.186208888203,20.32));
#872=VERTEX_POINT('',#871);
#873=EDGE_CURVE('E258',#872,#864,#870,.T.);
#874=ORIENTED_EDGE('',*,*,#873,.F.);
#875=CARTESIAN_POINT('',(46.1941016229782,-10.16,20.32));
#876=DIRECTION('',(0.,0.,-1.));
#877=DIRECTION('',(-1.,0.,0.));
#878=AXIS2_PLACEMENT_3D('',#875,#876,#877);
#879=CIRCLE('',#878,20.32);
#880=CARTESIAN_POINT('',(46.1941016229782,-30.48,20.32));
#881=VERTEX_POINT('',#880);
#882=EDGE_CURVE('E1051',#881,#872,#879,.F.);
#883=ORIENTED_EDGE('',*,*,#882,.F.);
#884=DIRECTION('',(-1.,0.,0.));
#885=VECTOR('',#884,1.);
#886=CARTESIAN_POINT('',(0.,-30.48,20.32));
#887=LINE('',#886,#885);
#888=CARTESIAN_POINT('',(5.08,-30.48,20.32));
#889=VERTEX_POINT('',#888);
#890=EDGE_CURVE('E1047',#889,#881,#887,.F.);
#891=ORIENTED_EDGE('',*,*,#890,.F.);
#892=DIRECTION('',(0.,1.,0.));
#893=VECTOR('',#892,1.);
#894=CARTESIAN_POINT('',(5.08,0.,20.32));
#895=LINE('',#894,#893);
#896=EDGE_CURVE('E275',#102,#889,#895,.F.);
#897=ORIENTED_EDGE('',*,*,#896,.F.);
#898=EDGE_LOOP('',(#858,#866,#874,#883,#891,#897));
#899=FACE_BOUND('',#898,.T.);
#900=ADVANCED_FACE('F834',(#899),#857,.T.);
#901=CARTESIAN_POINT('',(0.,0.,-20.32));
#902=DIRECTION('',(0.,0.,-1.));
#903=DIRECTION('',(-1.,0.,0.));
#904=AXIS2_PLACEMENT_3D('',#901,#902,#903);
#905=PLANE('',#904);
#906=DIRECTION('',(-1.,0.,0.));
#907=VECTOR('',#906,1.);
#908=CARTESIAN_POINT('',(0.,-30.48,-20.32));
#909=LINE('',#908,#907);
#910=CARTESIAN_POINT('',(46.1941016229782,-30.48,-20.32));
#911=VERTEX_POINT('',#910);
#912=CARTESIAN_POINT('',(5.08,-30.48,-20.32));
#913=VERTEX_POINT('',#912);
#914=EDGE_CURVE('E293',#911,#913,#909,.T.);
#915=ORIENTED_EDGE('',*,*,#914,.F.);
#916=CARTESIAN_POINT('',(46.1941016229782,-10.16,-20.32));
#917=DIRECTION('',(0.,0.,-1.));
#918=DIRECTION('',(-1.,0.,0.));
#919=AXIS2_PLACEMENT_3D('',#916,#917,#918);
#920=CIRCLE('',#919,20.32);
#921=CARTESIAN_POINT('',(53.3289299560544,-29.186208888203,-20.32));
#922=VERTEX_POINT('',#921);
#923=EDGE_CURVE('E296',#922,#911,#920,.T.);
#924=ORIENTED_EDGE('',*,*,#923,.F.);
#925=DIRECTION('',(-0.936329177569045,-0.351123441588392,0.));
#926=VECTOR('',#925,1.);
#927=CARTESIAN_POINT('',(99.816292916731,-11.7534477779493,-20.32));
#928=LINE('',#927,#926);
#929=CARTESIAN_POINT('',(96.52,-12.9895576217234,-20.32));
#930=VERTEX_POINT('',#929);
#931=EDGE_CURVE('E292',#930,#922,#928,.T.);
#932=ORIENTED_EDGE('',*,*,#931,.F.);
#933=DIRECTION('',(0.,1.,0.));
#934=VECTOR('',#933,1.);
#935=CARTESIAN_POINT('',(96.52,0.,-20.32));
#936=LINE('',#935,#934);
#937=EDGE_CURVE('E288',#127,#930,#936,.F.);
#938=ORIENTED_EDGE('',*,*,#937,.F.);
#939=ORIENTED_EDGE('',*,*,#128,.T.);
#940=DIRECTION('',(0.,1.,0.));
#941=VECTOR('',#940,1.);
#942=CARTESIAN_POINT('',(5.08,0.,-20.32));
#943=LINE('',#942,#941);
#944=EDGE_CURVE('E291',#913,#119,#943,.T.);
#945=ORIENTED_EDGE('',*,*,#944,.F.);
#946=EDGE_LOOP('',(#915,#924,#932,#938,#939,#945));
#947=FACE_BOUND('',#946,.T.);
#948=ADVANCED_FACE('F843',(#947),#905,.F.);
#949=CARTESIAN_POINT('',(96.52,-12.9895576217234,22.86));
#950=DIRECTION('',(0.,0.,-1.));
#951=DIRECTION('',(-1.,0.,0.));
#952=AXIS2_PLACEMENT_3D('',#949,#950,#951);
#953=CYLINDRICAL_SURFACE('',#952,2.54);
#954=ORIENTED_EDGE('',*,*,#842,.T.);
#955=CARTESIAN_POINT('',(96.52,-12.9895576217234,-17.78));
#956=DIRECTION('',(0.,0.,-1.));
#957=DIRECTION('',(-1.,0.,0.));
#958=AXIS2_PLACEMENT_3D('',#955,#956,#957);
#959=CIRCLE('',#958,2.54);
#960=EDGE_CURVE('E1113',#810,#833,#959,.F.);
#961=ORIENTED_EDGE('',*,*,#960,.F.);
#962=ORIENTED_EDGE('',*,*,#811,.T.);
#963=CARTESIAN_POINT('',(96.52,-12.9895576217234,17.78));
#964=DIRECTION('',(0.,0.,-1.));
#965=DIRECTION('',(-1.,0.,0.));
#966=AXIS2_PLACEMENT_3D('',#963,#964,#965);
#967=CIRCLE('',#966,2.54);
#968=EDGE_CURVE('E297',#841,#802,#967,.T.);
#969=ORIENTED_EDGE('',*,*,#968,.F.);
#970=EDGE_LOOP('',(#954,#961,#962,#969));
#971=FACE_BOUND('',#970,.T.);
#972=ADVANCED_FACE('F852',(#971),#953,.F.);
#973=CARTESIAN_POINT('',(5.08,-30.48,22.86));
#974=DIRECTION('',(0.,0.,-1.));
#975=DIRECTION('',(-1.,0.,0.));
#976=AXIS2_PLACEMENT_3D('',#973,#974,#975);
#977=CYLINDRICAL_SURFACE('',#976,2.54);
#978=ORIENTED_EDGE('',*,*,#771,.T.);
#979=CARTESIAN_POINT('',(5.08,-30.48,-17.78));
#980=DIRECTION('',(0.,0.,-1.));
#981=DIRECTION('',(-1.,0.,0.));
#982=AXIS2_PLACEMENT_3D('',#979,#980,#981);
#983=CIRCLE('',#982,2.54);
#984=EDGE_CURVE('E247',#721,#762,#983,.F.);
#985=ORIENTED_EDGE('',*,*,#984,.F.);
#986=ORIENTED_EDGE('',*,*,#724,.T.);
#987=CARTESIAN_POINT('',(5.08,-30.48,17.78));
#988=DIRECTION('',(0.,0.,-1.));
#989=DIRECTION('',(-1.,0.,0.));
#990=AXIS2_PLACEMENT_3D('',#987,#988,#989);
#991=CIRCLE('',#990,2.54);
#992=EDGE_CURVE('E236',#770,#723,#991,.T.);
#993=ORIENTED_EDGE('',*,*,#992,.F.);
#994=EDGE_LOOP('',(#978,#985,#986,#993));
#995=FACE_BOUND('',#994,.T.);
#996=ADVANCED_FACE('F253',(#995),#977,.F.);
#997=CARTESIAN_POINT('',(46.1941016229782,-10.16,22.86));
#998=DIRECTION('',(0.,0.,-1.));
#999=DIRECTION('',(-1.,0.,0.));
#1000=AXIS2_PLACEMENT_3D('',#997,#998,#999);
#1001=CYLINDRICAL_SURFACE('',#1000,22.86);
#1002=ORIENTED_EDGE('',*,*,#795,.T.);
#1003=CARTESIAN_POINT('',(46.1941016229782,-10.16,-17.78));
#1004=DIRECTION('',(0.,0.,-1.));
#1005=DIRECTION('',(-1.,0.,0.));
#1006=AXIS2_PLACEMENT_3D('',#1003,#1004,#1005);
#1007=CIRCLE('',#1006,22.86);
#1008=EDGE_CURVE('E1084',#752,#794,#1007,.F.);
#1009=ORIENTED_EDGE('',*,*,#1008,.F.);
#1010=ORIENTED_EDGE('',*,*,#755,.T.);
#1011=CARTESIAN_POINT('',(46.1941016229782,-10.16,17.78));
#1012=DIRECTION('',(0.,0.,-1.));
#1013=DIRECTION('',(-1.,0.,0.));
#1014=AXIS2_PLACEMENT_3D('',#1011,#1012,#1013);
#1015=CIRCLE('',#1014,22.86);
#1016=EDGE_CURVE('E1074',#792,#754,#1015,.T.);
#1017=ORIENTED_EDGE('',*,*,#1016,.F.);
#1018=EDGE_LOOP('',(#1002,#1009,#1010,#1017));
#1019=FACE_BOUND('',#1018,.T.);
#1020=ADVANCED_FACE('F868',(#1019),#1001,.F.);
#1021=CARTESIAN_POINT('',(96.52,0.,17.78));
#1022=DIRECTION('',(0.,1.,0.));
#1023=DIRECTION('',(0.,0.,1.));
#1024=AXIS2_PLACEMENT_3D('',#1021,#1022,#1023);
#1025=CYLINDRICAL_SURFACE('',#1024,2.54);
#1026=CARTESIAN_POINT('',(96.52,-12.9895576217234,17.78));
#1027=DIRECTION('',(0.,1.,0.));
#1028=DIRECTION('',(-1.,0.,0.));
#1029=AXIS2_PLACEMENT_3D('',#1026,#1027,#1028);
#1030=CIRCLE('',#1029,2.54);
#1031=EDGE_CURVE('E345',#841,#864,#1030,.F.);
#1032=ORIENTED_EDGE('',*,*,#1031,.T.);
#1033=ORIENTED_EDGE('',*,*,#865,.T.);
#1034=ORIENTED_EDGE('',*,*,#154,.T.);
#1035=ORIENTED_EDGE('',*,*,#848,.T.);
#1036=EDGE_LOOP('',(#1032,#1033,#1034,#1035));
#1037=FACE_BOUND('',#1036,.T.);
#1038=ADVANCED_FACE('F876',(#1037),#1025,.F.);
#1039=CARTESIAN_POINT('',(96.52,-12.9895576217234,17.78));
#1040=DIRECTION('',(0.,0.,-1.));
#1041=DIRECTION('',(-1.,0.,0.));
#1042=AXIS2_PLACEMENT_3D('',#1039,#1040,#1041);
#1043=SPHERICAL_SURFACE('',#1042,2.54);
#1044=ORIENTED_EDGE('',*,*,#968,.T.);
#1045=CARTESIAN_POINT('',(96.52,-12.9895576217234,17.78));
#1046=DIRECTION('',(0.936329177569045,0.351123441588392,0.));
#1047=DIRECTION('',(-0.351123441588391,0.936329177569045,0.));
#1048=AXIS2_PLACEMENT_3D('',#1045,#1046,#1047);
#1049=CIRCLE('',#1048,2.54);
#1050=EDGE_CURVE('E1061',#802,#864,#1049,.F.);
#1051=ORIENTED_EDGE('',*,*,#1050,.T.);
#1052=ORIENTED_EDGE('',*,*,#1031,.F.);
#1053=EDGE_LOOP('',(#1044,#1051,#1052));
#1054=FACE_BOUND('',#1053,.T.);
#1055=ADVANCED_FACE('F885',(#1054),#1043,.F.);
#1056=CARTESIAN_POINT('',(16.1702655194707,-43.1207080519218,17.78));
#1057=DIRECTION('',(0.936329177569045,0.351123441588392,0.));
#1058=DIRECTION('',(-0.351123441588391,0.936329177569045,0.));
#1059=AXIS2_PLACEMENT_3D('',#1056,#1057,#1058);
#1060=CYLINDRICAL_SURFACE('',#1059,2.54);
#1061=ORIENTED_EDGE('',*,*,#1050,.F.);
#1062=ORIENTED_EDGE('',*,*,#803,.T.);
#1063=CARTESIAN_POINT('',(53.3289299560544,-29.186208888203,17.78));
#1064=DIRECTION('',(0.936329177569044,0.351123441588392,0.));
#1065=DIRECTION('',(-0.351123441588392,0.936329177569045,0.));
#1066=AXIS2_PLACEMENT_3D('',#1063,#1064,#1065);
#1067=CIRCLE('',#1066,2.54);
#1068=EDGE_CURVE('E1065',#792,#872,#1067,.F.);
#1069=ORIENTED_EDGE('',*,*,#1068,.T.);
#1070=ORIENTED_EDGE('',*,*,#873,.T.);
#1071=EDGE_LOOP('',(#1061,#1062,#1069,#1070));
#1072=FACE_BOUND('',#1071,.T.);
#1073=ADVANCED_FACE('F894',(#1072),#1060,.F.);
#1074=CARTESIAN_POINT('',(46.1941016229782,-10.16,17.78));
#1075=DIRECTION('',(0.,0.,-1.));
#1076=DIRECTION('',(-1.,0.,0.));
#1077=AXIS2_PLACEMENT_3D('',#1074,#1075,#1076);
#1078=TOROIDAL_SURFACE('',#1077,20.32,2.54);
#1079=ORIENTED_EDGE('',*,*,#1068,.F.);
#1080=ORIENTED_EDGE('',*,*,#1016,.T.);
#1081=CARTESIAN_POINT('',(46.1941016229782,-30.48,17.78));
#1082=DIRECTION('',(1.,0.,0.));
#1083=DIRECTION('',(0.,1.,0.));
#1084=AXIS2_PLACEMENT_3D('',#1081,#1082,#1083);
#1085=CIRCLE('',#1084,2.54);
#1086=EDGE_CURVE('E281',#754,#881,#1085,.F.);
#1087=ORIENTED_EDGE('',*,*,#1086,.T.);
#1088=ORIENTED_EDGE('',*,*,#882,.T.);
#1089=EDGE_LOOP('',(#1079,#1080,#1087,#1088));
#1090=FACE_BOUND('',#1089,.T.);
#1091=ADVANCED_FACE('F905',(#1090),#1078,.F.);
#1092=CARTESIAN_POINT('',(0.,-30.48,17.78));
#1093=DIRECTION('',(1.,0.,0.));
#1094=DIRECTION('',(0.,1.,0.));
#1095=AXIS2_PLACEMENT_3D('',#1092,#1093,#1094);
#1096=CYLINDRICAL_SURFACE('',#1095,2.54);
#1097=CARTESIAN_POINT('',(5.08,-30.48,17.78));
#1098=DIRECTION('',(1.,0.,0.));
#1099=DIRECTION('',(0.,1.,0.));
#1100=AXIS2_PLACEMENT_3D('',#1097,#1098,#1099);
#1101=CIRCLE('',#1100,2.54);
#1102=EDGE_CURVE('E242',#770,#889,#1101,.F.);
#1103=ORIENTED_EDGE('',*,*,#1102,.T.);
#1104=ORIENTED_EDGE('',*,*,#890,.T.);
#1105=ORIENTED_EDGE('',*,*,#1086,.F.);
#1106=ORIENTED_EDGE('',*,*,#777,.T.);
#1107=EDGE_LOOP('',(#1103,#1104,#1105,#1106));
#1108=FACE_BOUND('',#1107,.T.);
#1109=ADVANCED_FACE('F914',(#1108),#1096,.F.);
#1110=CARTESIAN_POINT('',(5.08,-30.48,17.78));
#1111=DIRECTION('',(0.,0.,-1.));
#1112=DIRECTION('',(-1.,0.,0.));
#1113=AXIS2_PLACEMENT_3D('',#1110,#1111,#1112);
#1114=SPHERICAL_SURFACE('',#1113,2.54);
#1115=ORIENTED_EDGE('',*,*,#992,.T.);
#1116=CARTESIAN_POINT('',(5.08,-30.48,17.78));
#1117=DIRECTION('',(0.,-1.,0.));
#1118=DIRECTION('',(0.,0.,-1.));
#1119=AXIS2_PLACEMENT_3D('',#1116,#1117,#1118);
#1120=CIRCLE('',#1119,2.54);
#1121=EDGE_CURVE('E240',#723,#889,#1120,.F.);
#1122=ORIENTED_EDGE('',*,*,#1121,.T.);
#1123=ORIENTED_EDGE('',*,*,#1102,.F.);
#1124=EDGE_LOOP('',(#1115,#1122,#1123));
#1125=FACE_BOUND('',#1124,.T.);
#1126=ADVANCED_FACE('F238',(#1125),#1114,.F.);
#1127=CARTESIAN_POINT('',(5.08,0.,17.78));
#1128=DIRECTION('',(0.,-1.,0.));
#1129=DIRECTION('',(0.,0.,-1.));
#1130=AXIS2_PLACEMENT_3D('',#1127,#1128,#1129);
#1131=CYLINDRICAL_SURFACE('',#1130,2.54);
#1132=ORIENTED_EDGE('',*,*,#103,.T.);
#1133=ORIENTED_EDGE('',*,*,#896,.T.);
#1134=ORIENTED_EDGE('',*,*,#1121,.F.);
#1135=ORIENTED_EDGE('',*,*,#737,.T.);
#1136=EDGE_LOOP('',(#1132,#1133,#1134,#1135));
#1137=FACE_BOUND('',#1136,.T.);
#1138=ADVANCED_FACE('F273',(#1137),#1131,.F.);
#1139=CARTESIAN_POINT('',(96.52,0.,-17.78));
#1140=DIRECTION('',(0.,-1.,0.));
#1141=DIRECTION('',(0.,0.,-1.));
#1142=AXIS2_PLACEMENT_3D('',#1139,#1140,#1141);
#1143=CYLINDRICAL_SURFACE('',#1142,2.54);
#1144=ORIENTED_EDGE('',*,*,#137,.T.);
#1145=ORIENTED_EDGE('',*,*,#937,.T.);
#1146=CARTESIAN_POINT('',(96.52,-12.9895576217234,-17.78));
#1147=DIRECTION('',(0.,1.,0.));
#1148=DIRECTION('',(-1.,0.,0.));
#1149=AXIS2_PLACEMENT_3D('',#1146,#1147,#1148);
#1150=CIRCLE('',#1149,2.54);
#1151=EDGE_CURVE('E277',#930,#833,#1150,.F.);
#1152=ORIENTED_EDGE('',*,*,#1151,.T.);
#1153=ORIENTED_EDGE('',*,*,#834,.T.);
#1154=EDGE_LOOP('',(#1144,#1145,#1152,#1153));
#1155=FACE_BOUND('',#1154,.T.);
#1156=ADVANCED_FACE('F942',(#1155),#1143,.F.);
#1157=CARTESIAN_POINT('',(96.52,-12.9895576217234,-17.78));
#1158=DIRECTION('',(0.,0.,-1.));
#1159=DIRECTION('',(-1.,0.,0.));
#1160=AXIS2_PLACEMENT_3D('',#1157,#1158,#1159);
#1161=SPHERICAL_SURFACE('',#1160,2.54);
#1162=ORIENTED_EDGE('',*,*,#1151,.F.);
#1163=CARTESIAN_POINT('',(96.52,-12.9895576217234,-17.78));
#1164=DIRECTION('',(-0.936329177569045,-0.351123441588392,0.));
#1165=DIRECTION('',(0.351123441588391,-0.936329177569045,0.));
#1166=AXIS2_PLACEMENT_3D('',#1163,#1164,#1165);
#1167=CIRCLE('',#1166,2.54);
#1168=EDGE_CURVE('E284',#930,#810,#1167,.T.);
#1169=ORIENTED_EDGE('',*,*,#1168,.T.);
#1170=ORIENTED_EDGE('',*,*,#960,.T.);
#1171=EDGE_LOOP('',(#1162,#1169,#1170));
#1172=FACE_BOUND('',#1171,.T.);
#1173=ADVANCED_FACE('F950',(#1172),#1161,.F.);
#1174=CARTESIAN_POINT('',(99.816292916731,-11.7534477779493,-17.78));
#1175=DIRECTION('',(-0.936329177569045,-0.351123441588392,0.));
#1176=DIRECTION('',(0.351123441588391,-0.936329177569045,0.));
#1177=AXIS2_PLACEMENT_3D('',#1174,#1175,#1176);
#1178=CYLINDRICAL_SURFACE('',#1177,2.54);
#1179=ORIENTED_EDGE('',*,*,#1168,.F.);
#1180=ORIENTED_EDGE('',*,*,#931,.T.);
#1181=CARTESIAN_POINT('',(53.3289299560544,-29.186208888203,-17.78));
#1182=DIRECTION('',(0.936329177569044,0.351123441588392,0.));
#1183=DIRECTION('',(-0.351123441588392,0.936329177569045,0.));
#1184=AXIS2_PLACEMENT_3D('',#1181,#1182,#1183);
#1185=CIRCLE('',#1184,2.54);
#1186=EDGE_CURVE('E308',#922,#794,#1185,.F.);
#1187=ORIENTED_EDGE('',*,*,#1186,.T.);
#1188=ORIENTED_EDGE('',*,*,#817,.T.);
#1189=EDGE_LOOP('',(#1179,#1180,#1187,#1188));
#1190=FACE_BOUND('',#1189,.T.);
#1191=ADVANCED_FACE('F959',(#1190),#1178,.F.);
#1192=CARTESIAN_POINT('',(46.1941016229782,-10.16,-17.78));
#1193=DIRECTION('',(0.,0.,-1.));
#1194=DIRECTION('',(-1.,0.,0.));
#1195=AXIS2_PLACEMENT_3D('',#1192,#1193,#1194);
#1196=TOROIDAL_SURFACE('',#1195,20.32,2.54);
#1197=ORIENTED_EDGE('',*,*,#1186,.F.);
#1198=ORIENTED_EDGE('',*,*,#923,.T.);
#1199=CARTESIAN_POINT('',(46.1941016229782,-30.48,-17.78));
#1200=DIRECTION('',(-1.,0.,0.));
#1201=DIRECTION('',(0.,-1.,0.));
#1202=AXIS2_PLACEMENT_3D('',#1199,#1200,#1201);
#1203=CIRCLE('',#1202,2.54);
#1204=EDGE_CURVE('E312',#911,#752,#1203,.T.);
#1205=ORIENTED_EDGE('',*,*,#1204,.T.);
#1206=ORIENTED_EDGE('',*,*,#1008,.T.);
#1207=EDGE_LOOP('',(#1197,#1198,#1205,#1206));
#1208=FACE_BOUND('',#1207,.T.);
#1209=ADVANCED_FACE('F970',(#1208),#1196,.F.);
#1210=CARTESIAN_POINT('',(50.8,-30.48,-17.78));
#1211=DIRECTION('',(-1.,0.,0.));
#1212=DIRECTION('',(0.,-1.,0.));
#1213=AXIS2_PLACEMENT_3D('',#1210,#1211,#1212);
#1214=CYLINDRICAL_SURFACE('',#1213,2.54);
#1215=ORIENTED_EDGE('',*,*,#1204,.F.);
#1216=ORIENTED_EDGE('',*,*,#914,.T.);
#1217=CARTESIAN_POINT('',(5.08,-30.48,-17.78));
#1218=DIRECTION('',(1.,0.,0.));
#1219=DIRECTION('',(0.,1.,0.));
#1220=AXIS2_PLACEMENT_3D('',#1217,#1218,#1219);
#1221=CIRCLE('',#1220,2.54);
#1222=EDGE_CURVE('E316',#913,#762,#1221,.F.);
#1223=ORIENTED_EDGE('',*,*,#1222,.T.);
#1224=ORIENTED_EDGE('',*,*,#763,.T.);
#1225=EDGE_LOOP('',(#1215,#1216,#1223,#1224));
#1226=FACE_BOUND('',#1225,.T.);
#1227=ADVANCED_FACE('F979',(#1226),#1214,.F.);
#1228=CARTESIAN_POINT('',(5.08,-30.48,-17.78));
#1229=DIRECTION('',(0.,0.,-1.));
#1230=DIRECTION('',(-1.,0.,0.));
#1231=AXIS2_PLACEMENT_3D('',#1228,#1229,#1230);
#1232=SPHERICAL_SURFACE('',#1231,2.54);
#1233=ORIENTED_EDGE('',*,*,#1222,.F.);
#1234=CARTESIAN_POINT('',(5.08,-30.48,-17.78));
#1235=DIRECTION('',(0.,1.,0.));
#1236=DIRECTION('',(0.,0.,1.));
#1237=AXIS2_PLACEMENT_3D('',#1234,#1235,#1236);
#1238=CIRCLE('',#1237,2.54);
#1239=EDGE_CURVE('E320',#913,#721,#1238,.T.);
#1240=ORIENTED_EDGE('',*,*,#1239,.T.);
#1241=ORIENTED_EDGE('',*,*,#984,.T.);
#1242=EDGE_LOOP('',(#1233,#1240,#1241));
#1243=FACE_BOUND('',#1242,.T.);
#1244=ADVANCED_FACE('F990',(#1243),#1232,.F.);
#1245=CARTESIAN_POINT('',(5.08,-35.56,-17.78));
#1246=DIRECTION('',(0.,1.,0.));
#1247=DIRECTION('',(0.,0.,1.));
#1248=AXIS2_PLACEMENT_3D('',#1245,#1246,#1247);
#1249=CYLINDRICAL_SURFACE('',#1248,2.54);
#1250=ORIENTED_EDGE('',*,*,#120,.T.);
#1251=ORIENTED_EDGE('',*,*,#730,.T.);
#1252=ORIENTED_EDGE('',*,*,#1239,.F.);
#1253=ORIENTED_EDGE('',*,*,#944,.T.);
#1254=EDGE_LOOP('',(#1250,#1251,#1252,#1253));
#1255=FACE_BOUND('',#1254,.T.);
#1256=ADVANCED_FACE('F999',(#1255),#1249,.F.);
#1257=CLOSED_SHELL('',(#164,#195,#235,#275,#306,#354,#402,#426,#450,#474,#492,#509,#527,#545,
#563,#580,#592,#610,#627,#645,#663,#681,#698,#710,#741,#781,#821,#852,#900,#948,#972,#996,#1020,
#1038,#1055,#1073,#1091,#1109,#1126,#1138,#1156,#1173,#1191,#1209,#1227,#1244,#1256));
#1258=MANIFOLD_SOLID_BREP('B2',#1257);
#1259=ADVANCED_BREP_SHAPE_REPRESENTATION('',(#18,#1258),#14);
#1260=SHAPE_DEFINITION_REPRESENTATION(#9,#1259);
ENDSEC;
END-ISO-10303-21;
